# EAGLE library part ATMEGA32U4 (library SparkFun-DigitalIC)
Atmel 44-pin 8-bit Microcontroller with 32KBytes of ISP Flash and USB Controller

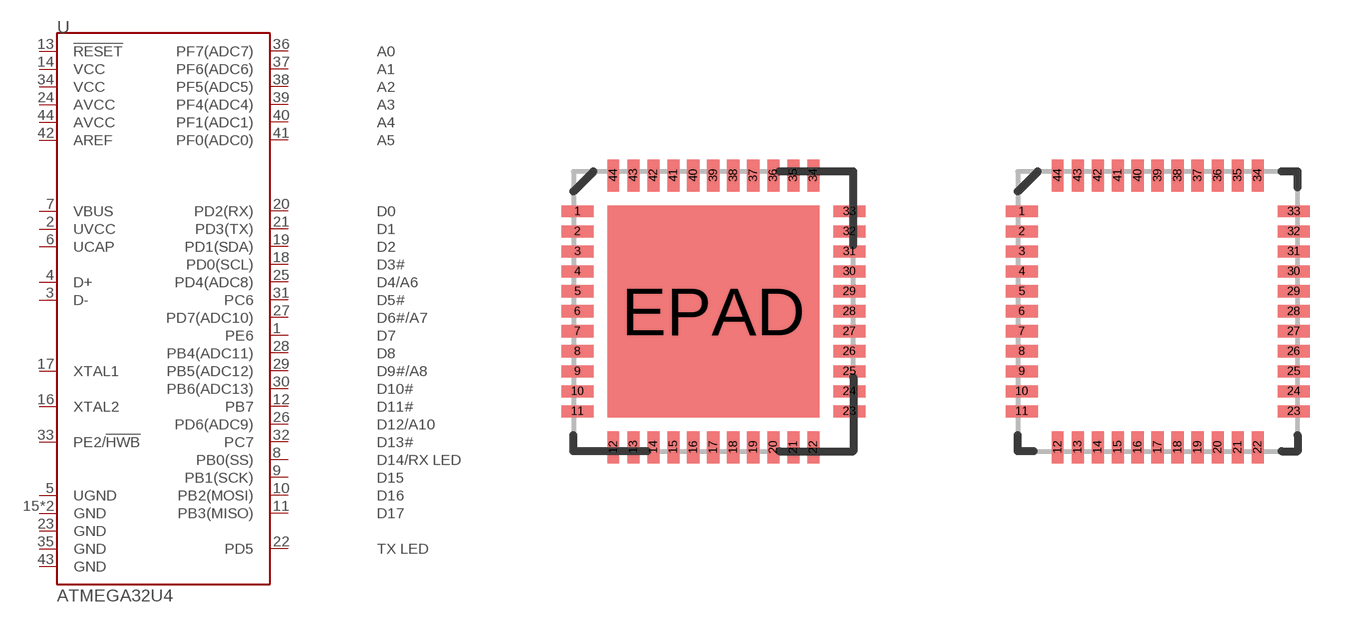
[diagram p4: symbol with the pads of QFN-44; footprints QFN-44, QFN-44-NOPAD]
Designator prefix -

## ATMEGA32U4QFN  [QFN-44]
1  PE6
2  UVCC
3  D-
4  D+
5  UGND
6  UCAP
7  VBUS
8  PB0(SS)
9  PB1(SCK)
10  PB2(MOSI)
11  PB3(MISO)
12  PB7
13  !RESET
14  VCC
15  GND
16  XTAL2
17  XTAL1
18  PD0(SCL)
19  PD1(SDA)
20  PD2(RX)
21  PD3(TX)
22  PD5
23  GND
24  AVCC
25  PD4(ADC8)
26  PD6(ADC9)
27  PD7(ADC10)
28  PB4(ADC11)
29  PB5(ADC12)
30  PB6(ADC13)
31  PC6
32  PC7
33  PE2/!HWB
34  VCC
35  GND
36  PF7(ADC7)
37  PF6(ADC6)
38  PF5(ADC5)
39  PF4(ADC4)
40  PF1(ADC1)
41  PF0(ADC0)
42  AREF
43  GND
44  AVCC
EPAD  GND

## ATMEGA32U4QFN2  [QFN-44-NOPAD]
1  PE6
2  UVCC
3  D-
4  D+
5  UGND
6  UCAP
7  VBUS
8  PB0(SS)
9  PB1(SCK)
10  PB2(MOSI)
11  PB3(MISO)
12  PB7
13  !RESET
14  VCC
15  GND
16  XTAL2
17  XTAL1
18  PD0(SCL)
19  PD1(SDA)
20  PD2(RX)
21  PD3(TX)
22  PD5
23  GND
24  AVCC
25  PD4(ADC8)
26  PD6(ADC9)
27  PD7(ADC10)
28  PB4(ADC11)
29  PB5(ADC12)
30  PB6(ADC13)
31  PC6
32  PC7
33  PE2/!HWB
34  VCC
35  GND
36  PF7(ADC7)
37  PF6(ADC6)
38  PF5(ADC5)
39  PF4(ADC4)
40  PF1(ADC1)
41  PF0(ADC0)
42  AREF
43  GND
44  AVCC

## Footprint QFN-44 (pad centres in mm)
smd 0.8 x 0.3: 1 -3.4,2.5; 2 -3.4,2; 3 -3.4,1.5; 4 -3.4,1; 5 -3.4,0.5; 6 -3.4,0; 7 -3.4,-0.5; 8 -3.4,-1; 9 -3.4,-1.5; 10 -3.4,-2; 11 -3.4,-2.5; 23 3.4,-2.5; 24 3.4,-2; 25 3.4,-1.5; 26 3.4,-1; 27 3.4,-0.5; 28 3.4,0; 29 3.4,0.5; 30 3.4,1; 31 3.4,1.5; 32 3.4,2; 33 3.4,2.5
smd 0.3 x 0.8: 12 -2.5,-3.4; 13 -2,-3.4; 14 -1.5,-3.4; 15 -1,-3.4; 16 -0.5,-3.4; 17 0,-3.4; 18 0.5,-3.4; 19 1,-3.4; 20 1.5,-3.4; 21 2,-3.4; 22 2.5,-3.4; 34 2.5,3.4; 35 2,3.4; 36 1.5,3.4; 37 1,3.4; 38 0.5,3.4; 39 0,3.4; 40 -0.5,3.4; 41 -1,3.4; 42 -1.5,3.4; 43 -2,3.4; 44 -2.5,3.4
smd 5.3 x 5.3: EPAD 0,0

## Footprint QFN-44-NOPAD (pad centres in mm)
smd 0.8 x 0.3: 1 -3.4,2.5; 2 -3.4,2; 3 -3.4,1.5; 4 -3.4,1; 5 -3.4,0.5; 6 -3.4,0; 7 -3.4,-0.5; 8 -3.4,-1; 9 -3.4,-1.5; 10 -3.4,-2; 11 -3.4,-2.5; 23 3.4,-2.5; 24 3.4,-2; 25 3.4,-1.5; 26 3.4,-1; 27 3.4,-0.5; 28 3.4,0; 29 3.4,0.5; 30 3.4,1; 31 3.4,1.5; 32 3.4,2; 33 3.4,2.5
smd 0.3 x 0.8: 12 -2.5,-3.4; 13 -2,-3.4; 14 -1.5,-3.4; 15 -1,-3.4; 16 -0.5,-3.4; 17 0,-3.4; 18 0.5,-3.4; 19 1,-3.4; 20 1.5,-3.4; 21 2,-3.4; 22 2.5,-3.4; 34 2.5,3.4; 35 2,3.4; 36 1.5,3.4; 37 1,3.4; 38 0.5,3.4; 39 0,3.4; 40 -0.5,3.4; 41 -1,3.4; 42 -1.5,3.4; 43 -2,3.4; 44 -2.5,3.4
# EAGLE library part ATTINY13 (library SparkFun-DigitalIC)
Atmel 8-pin 1kB flash uC

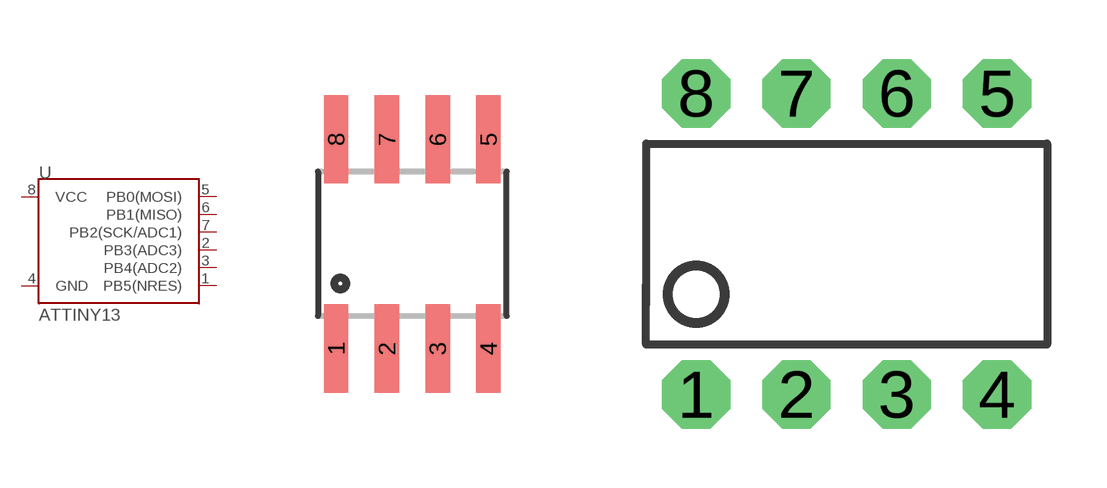
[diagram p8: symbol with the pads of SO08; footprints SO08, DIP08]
Designator prefix -

## ATTINY13SOIC  [SO08]
1  PB5(NRES)
2  PB3(ADC3)
3  PB4(ADC2)
4  GND
5  PB0(MOSI)
6  PB1(MISO)
7  PB2(SCK/ADC1)
8  VCC

## ATTINY13DIP  [DIP08]
Pads as for SO08

## Footprint SO08 (pad centres in mm)
Small Outline Package Fits JEDEC packages (narrow SOIC-8)
smd 0.61 x 2.21: 1 -1.905,-2.616; 2 -0.635,-2.616; 3 0.635,-2.616; 4 1.905,-2.616; 5 1.905,2.616; 6 0.635,2.616; 7 -0.635,2.616; 8 -1.905,2.616

## Footprint DIP08 (pad centres in mm)
Dual In Line
drill 0.813 pad 1.727 octagon: 1 -3.81,-3.81; 2 -1.27,-3.81; 3 1.27,-3.81; 4 3.81,-3.81; 5 3.81,3.81; 6 1.27,3.81; 7 -1.27,3.81; 8 -3.81,3.81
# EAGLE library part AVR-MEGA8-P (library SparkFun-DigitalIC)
MICROCONTROLLER 8 Kbytes FLASH 1 kbytes SRAM 512 bytes EEPROM USART 4-channel 10 bit ADC 2-channel 8 bit ADC

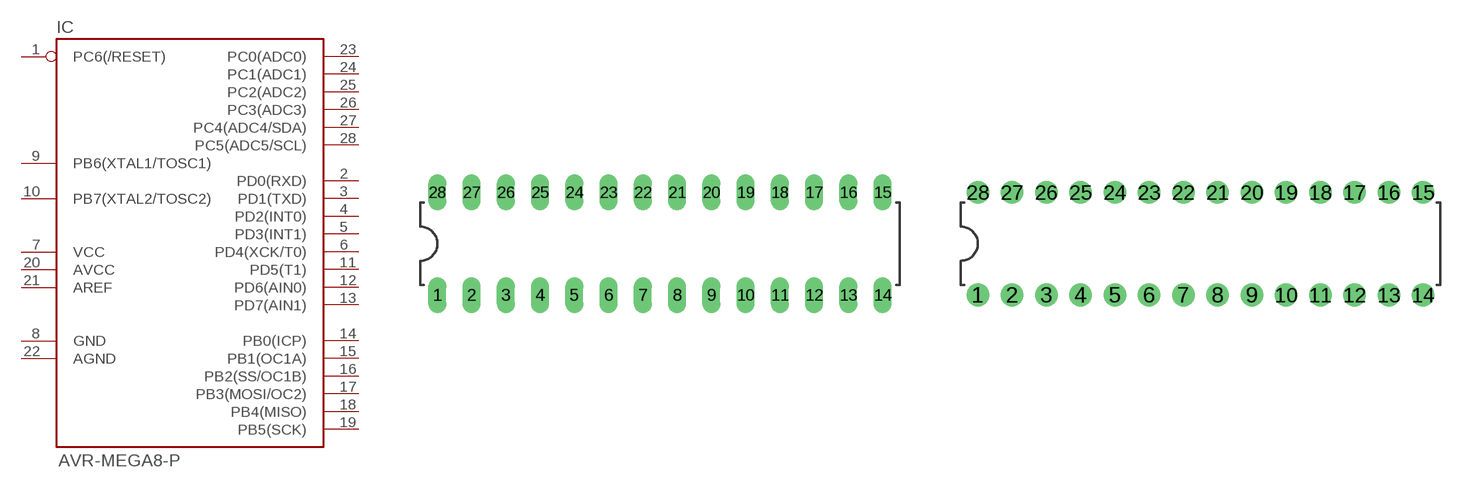
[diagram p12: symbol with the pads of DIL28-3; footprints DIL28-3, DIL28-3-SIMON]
Designator prefix IC

## AVR-MEGA8-PPTH  [DIL28-3]
1  PC6(/RESET)
2  PD0(RXD)
3  PD1(TXD)
4  PD2(INT0)
5  PD3(INT1)
6  PD4(XCK/T0)
7  VCC
8  GND
9  PB6(XTAL1/TOSC1)
10  PB7(XTAL2/TOSC2)
11  PD5(T1)
12  PD6(AIN0)
13  PD7(AIN1)
14  PB0(ICP)
15  PB1(OC1A)
16  PB2(SS/OC1B)
17  PB3(MOSI/OC2)
18  PB4(MISO)
19  PB5(SCK)
20  AVCC
21  AREF
22  AGND
23  PC0(ADC0)
24  PC1(ADC1)
25  PC2(ADC2)
26  PC3(ADC3)
27  PC4(ADC4/SDA)
28  PC5(ADC5/SCL)

## AVR-MEGA8-PSIM  [DIL28-3-SIMON]
Pads as for DIL28-3

## AVR-MEGA8-PZIF_SOCKET  [DIL28-3-ZIF_SOCKET]
Pads as for DIL28-3

## AVR-MEGA8-PKIT  [DIL28-3-SIMON-KIT]
Pads as for DIL28-3

## Footprint DIL28-3 (pad centres in mm)
Standard 28-pin DIP package. IC needs to have legs bent before insertion.
drill 0.813 long: 1 -16.51,-3.81; 2 -13.97,-3.81; 3 -11.43,-3.81; 4 -8.89,-3.81; 5 -6.35,-3.81; 6 -3.81,-3.81; 7 -1.27,-3.81; 8 1.27,-3.81; 9 3.81,-3.81; 10 6.35,-3.81; 11 8.89,-3.81; 12 11.43,-3.81; 13 13.97,-3.81; 14 16.51,-3.81; 15 16.51,3.81; 16 13.97,3.81; 17 11.43,3.81; 18 8.89,3.81; 19 6.35,3.81; 20 3.81,3.81; 21 1.27,3.81; 22 -1.27,3.81; 23 -3.81,3.81; 24 -6.35,3.81; 25 -8.89,3.81; 26 -11.43,3.81; 27 -13.97,3.81; 28 -16.51,3.81

## Footprint DIL28-3-SIMON (pad centres in mm)
drill 0.813 pad 1.676: 1 -16.51,-3.81; 2 -13.97,-3.81; 3 -11.43,-3.81; 4 -8.89,-3.81; 5 -6.35,-3.81; 6 -3.81,-3.81; 7 -1.27,-3.81; 8 1.27,-3.81; 9 3.81,-3.81; 10 6.35,-3.81; 11 8.89,-3.81; 12 11.43,-3.81; 13 13.97,-3.81; 14 16.51,-3.81; 15 16.51,3.81; 16 13.97,3.81; 17 11.43,3.81; 18 8.89,3.81; 19 6.35,3.81; 20 3.81,3.81; 21 1.27,3.81; 22 -1.27,3.81; 23 -3.81,3.81; 24 -6.35,3.81; 25 -8.89,3.81; 26 -11.43,3.81; 27 -13.97,3.81; 28 -16.51,3.81

## Footprint DIL28-3-ZIF_SOCKET (pad centres in mm)
drill 1.016 pad 1.88: 1 -16.51,-3.81; 2 -13.97,-3.81; 3 -11.43,-3.81; 4 -8.89,-3.81; 5 -6.35,-3.81; 6 -3.81,-3.81; 7 -1.27,-3.81; 8 1.27,-3.81; 9 3.81,-3.81; 10 6.35,-3.81; 11 8.89,-3.81; 12 11.43,-3.81; 13 13.97,-3.81; 14 16.51,-3.81; 15 16.51,3.81; 16 13.97,3.81; 17 11.43,3.81; 18 8.89,3.81; 19 6.35,3.81; 20 3.81,3.81; 21 1.27,3.81; 22 -1.27,3.81; 23 -3.81,3.81; 24 -6.35,3.81; 25 -8.89,3.81; 26 -11.43,3.81; 27 -13.97,3.81; 28 -16.51,3.81

## Footprint DIL28-3-SIMON-KIT (pad centres in mm)
DIL-28-3-SIMON-KIT 28-pin DIL package Used for the ATmega328 on our Simon Kit Warning: This is the KIT version of this package. This package has a smaller diameter top stop mask, which doesn't cover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
drill 0.864 pad 1.905: 1 -16.51,-4.255; 2 -13.97,-4.255; 3 -11.43,-4.255; 4 -8.89,-4.255; 5 -6.35,-4.255; 6 -3.81,-4.255; 7 -1.27,-4.255; 8 1.27,-4.255; 9 3.81,-4.255; 10 6.35,-4.255; 11 8.89,-4.255; 12 11.43,-4.255; 13 13.97,-4.255; 14 16.51,-4.255; 15 16.51,4.191; 16 13.97,4.191; 17 11.43,4.191; 18 8.89,4.191; 19 6.35,4.191; 20 3.81,4.191; 21 1.27,4.191; 22 -1.27,4.191; 23 -3.81,4.191; 24 -6.35,4.191; 25 -8.89,4.191; 26 -11.43,4.191; 27 -13.97,4.191; 28 -16.51,4.191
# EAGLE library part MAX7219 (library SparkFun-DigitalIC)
8-digit, 8-segment LED display driver, serial input

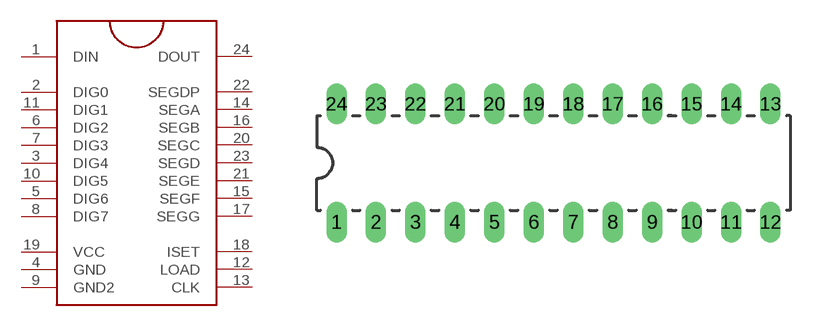
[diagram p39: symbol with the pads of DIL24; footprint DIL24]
Designator prefix -

## MAX7219DIP  [DIL24]
1  DIN
2  DIG0
3  DIG4
4  GND
5  DIG6
6  DIG2
7  DIG3
8  DIG7
9  GND2
10  DIG5
11  DIG1
12  LOAD
13  CLK
14  SEGA
15  SEGF
16  SEGB
17  SEGG
18  ISET
19  VCC
20  SEGC
21  SEGE
22  SEGDP
23  SEGD
24  DOUT

## Footprint DIL24 (pad centres in mm)
drill 0.813 long: 1 -13.97,-3.81; 2 -11.43,-3.81; 3 -8.89,-3.81; 4 -6.35,-3.81; 5 -3.81,-3.81; 6 -1.27,-3.81; 7 1.27,-3.81; 8 3.81,-3.81; 9 6.35,-3.81; 10 8.89,-3.81; 11 11.43,-3.81; 12 13.97,-3.81; 13 13.97,3.81; 14 11.43,3.81; 15 8.89,3.81; 16 6.35,3.81; 17 3.81,3.81; 18 1.27,3.81; 19 -1.27,3.81; 20 -3.81,3.81; 21 -6.35,3.81; 22 -8.89,3.81; 23 -11.43,3.81; 24 -13.97,3.81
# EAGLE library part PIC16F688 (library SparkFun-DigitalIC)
PIC 16F688 8-Bit PIC16F88

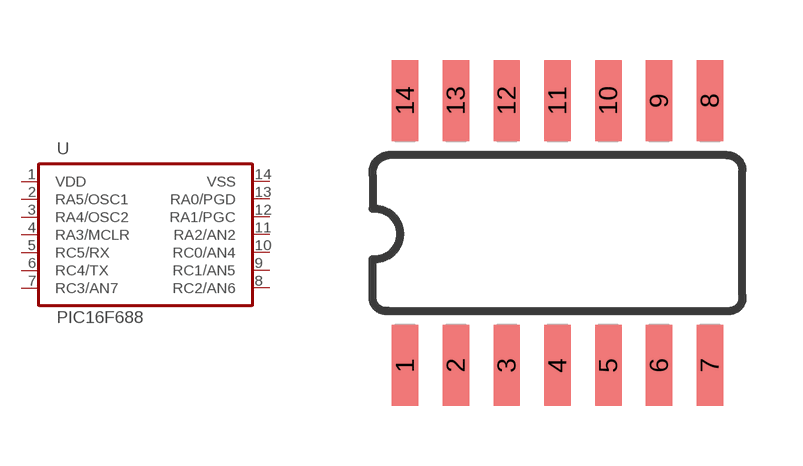
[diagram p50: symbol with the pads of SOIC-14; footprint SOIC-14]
Designator prefix -

## PIC16F688SMD  [SOIC-14]
1  VDD  pwr
2  RA5/OSC1
3  RA4/OSC2
4  RA3/MCLR
5  RC5/RX
6  RC4/TX
7  RC3/AN7
8  RC2/AN6
9  RC1/AN5
10  RC0/AN4
11  RA2/AN2
12  RA1/PGC
13  RA0/PGD
14  VSS  pwr

## Footprint SOIC-14 (pad centres in mm)
smd 0.66 x 2.032: 1 -4.445,-3.315; 2 -3.175,-3.315; 3 -1.905,-3.315; 4 -0.635,-3.315; 5 0.635,-3.315; 6 1.905,-3.315; 7 3.175,-3.315; 8 3.175,3.315; 9 1.905,3.315; 10 0.635,3.315; 11 -0.635,3.315; 12 -1.905,3.315; 13 -3.175,3.315; 14 -4.445,3.315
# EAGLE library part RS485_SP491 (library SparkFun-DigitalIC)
RS485 transceiver

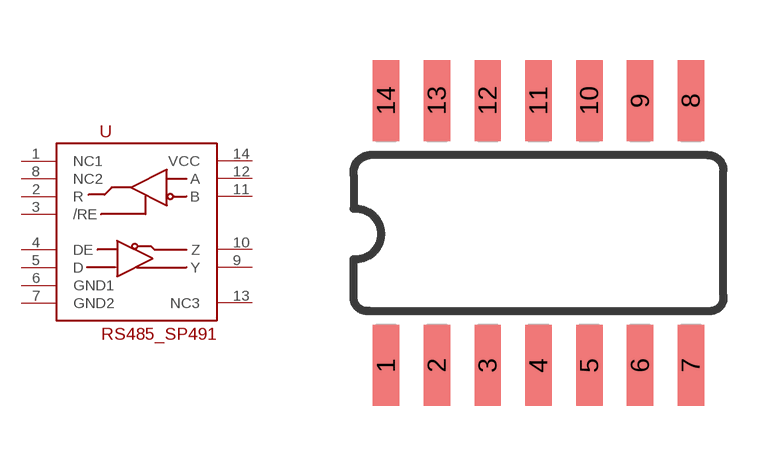
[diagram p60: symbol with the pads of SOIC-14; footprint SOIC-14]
Designator prefix -

## RS485_SP491  [SOIC-14]
1  NC1
2  R
3  /RE
4  DE
5  D
6  GND1
7  GND2
8  NC2
9  Y
10  Z
11  B
12  A
13  NC3
14  VCC

## Footprint SOIC-14 (pad centres in mm)
smd 0.66 x 2.032: 1 -4.445,-3.315; 2 -3.175,-3.315; 3 -1.905,-3.315; 4 -0.635,-3.315; 5 0.635,-3.315; 6 1.905,-3.315; 7 3.175,-3.315; 8 3.175,3.315; 9 1.905,3.315; 10 0.635,3.315; 11 -0.635,3.315; 12 -1.905,3.315; 13 -3.175,3.315; 14 -4.445,3.315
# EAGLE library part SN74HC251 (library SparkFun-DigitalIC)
SN54HC251 Data Selector/Multiplexer

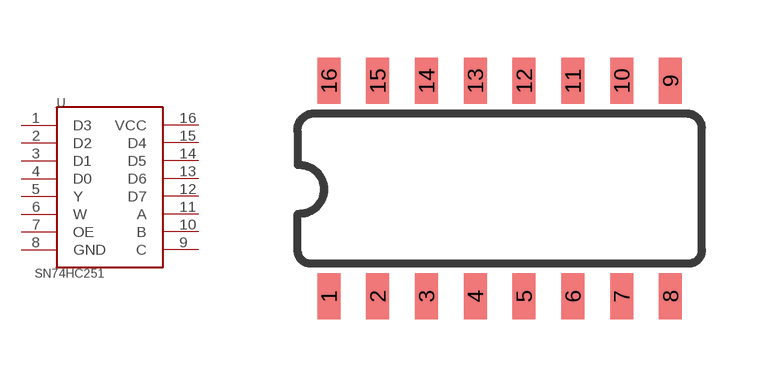
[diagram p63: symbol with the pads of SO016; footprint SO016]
Designator prefix U

## SN74HC251_SMD  [SO016]
1  D3
2  D2
3  D1
4  D0
5  Y
6  W
7  OE
8  GND
9  C
10  B
11  A
12  D7
13  D6
14  D5
15  D4
16  VCC

## Footprint SO016 (pad centres in mm)
smd 0.6 x 1.2: 1 -4.445,-2.8; 2 -3.175,-2.8; 3 -1.905,-2.8; 4 -0.635,-2.8; 5 0.635,-2.8; 6 1.905,-2.8; 7 3.175,-2.8; 8 4.445,-2.8; 9 4.445,2.8; 10 3.175,2.8; 11 1.905,2.8; 12 0.635,2.8; 13 -0.635,2.8; 14 -1.905,2.8; 15 -3.175,2.8; 16 -4.445,2.8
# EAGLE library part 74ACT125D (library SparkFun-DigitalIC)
Quad Buffer with 3-State Outputs- ON Semi Conductor: Digikey P/N MC74ACT125DR2GOSTR-ND

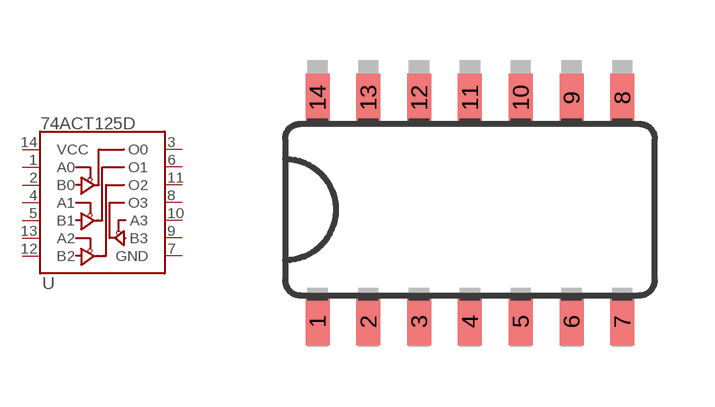
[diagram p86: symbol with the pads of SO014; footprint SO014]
Designator prefix -

## 74ACT125D  [SO014]
1  A0
2  B0
3  O0
4  A1
5  B1
6  O1
7  GND
8  O3
9  B3
10  A3
11  O2
12  B2
13  A2
14  VCC

## Footprint SO014 (pad centres in mm)
smd 0.6 x 1.2: 1 -3.175,-2.8; 2 -1.905,-2.8; 3 -0.635,-2.8; 4 0.635,-2.8; 5 1.905,-2.8; 6 3.175,-2.8; 7 4.445,-2.8; 8 4.445,2.8; 9 3.175,2.8; 10 1.905,2.8; 11 0.635,2.8; 12 -0.635,2.8; 13 -1.905,2.8; 14 -3.175,2.8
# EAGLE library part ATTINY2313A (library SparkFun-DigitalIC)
ATTINY2313A 2kB 20MHz I2C/SPI/UART

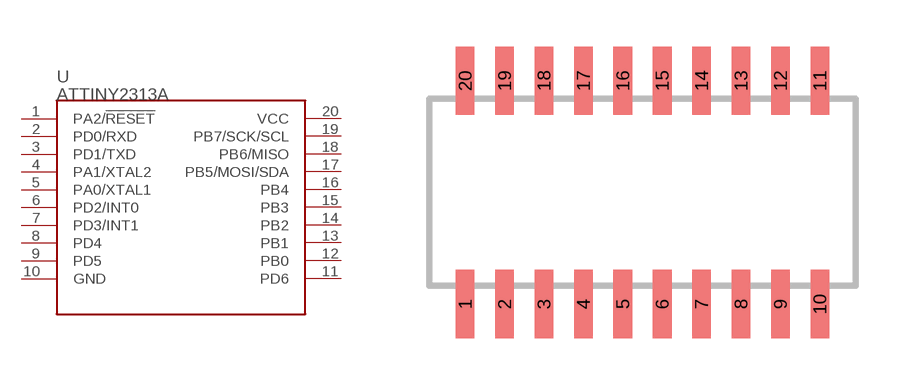
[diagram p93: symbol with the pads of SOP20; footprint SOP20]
Designator prefix -

## ATTINY2313A  [SOP20]
1  PA2/!RESET
2  PD0/RXD
3  PD1/TXD
4  PA1/XTAL2
5  PA0/XTAL1
6  PD2/INT0
7  PD3/INT1
8  PD4
9  PD5
10  GND
11  PD6
12  PB0
13  PB1
14  PB2
15  PB3
16  PB4
17  PB5/MOSI/SDA
18  PB6/MISO
19  PB7/SCK/SCL
20  VCC

## Footprint SOP20 (pad centres in mm)
SMALL OUTLINE PACKAGE
smd 0.6 x 2.2: 1 -5.715,-3.6; 2 -4.445,-3.6; 3 -3.175,-3.6; 4 -1.905,-3.6; 5 -0.635,-3.6; 6 0.635,-3.6; 7 1.905,-3.6; 8 3.175,-3.6; 9 4.445,-3.6; 10 5.715,-3.6; 11 5.715,3.6; 12 4.445,3.6; 13 3.175,3.6; 14 1.905,3.6; 15 0.635,3.6; 16 -0.635,3.6; 17 -1.905,3.6; 18 -3.175,3.6; 19 -4.445,3.6; 20 -5.715,3.6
